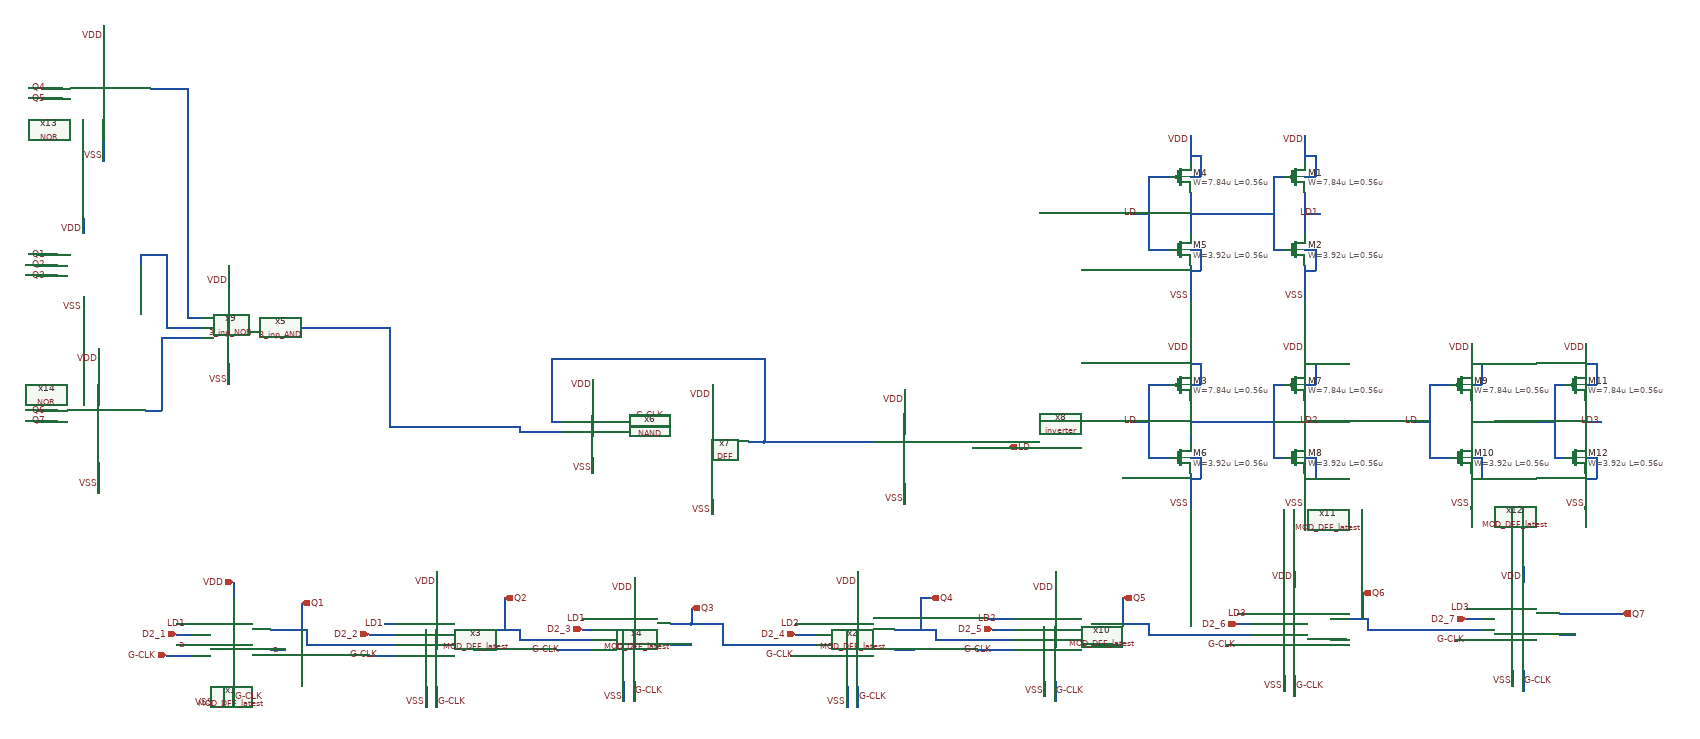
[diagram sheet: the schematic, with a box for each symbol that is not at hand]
v {xschem version=3.1.0 file_version=1.2
}
G {}
K {}
V {}
S {}
E {}
N -1260 -460 -1230 -460 {
lab=a}
N -1440 -490 -1410 -490 {
lab=D2_1}
N -1440 -470 -1410 -470 {
lab=a}
N -1330 -590 -1330 -560 {
lab=VDD}
N -1350 -390 -1350 -360 {
lab=VSS}
N 90 -850 130 -850 {
lab=LD}
N -1440 -510 -1410 -510 {
lab=LD1}
N -1040 -510 -1020 -510 {
lab=LD1}
N -1710 -1220 -1670 -1220 {
lab=Q1}
N -780 -880 -700 -880 {
lab=#net1}
N -310 -1020 -310 -860 {
lab=#net2}
N -720 -1020 -720 -900 {
lab=#net2}
N -720 -900 -700 -900 {
lab=#net2}
N -310 -860 -250 -860 {
lab=#net2}
N -410 -970 -410 -940 {
lab=VDD}
N -640 -980 -640 -950 {
lab=VDD}
N -640 -830 -640 -800 {
lab=VSS}
N -410 -750 -410 -720 {
lab=VSS}
N -940 -610 -940 -560 {
lab=VDD}
N -490 -470 -450 -470 {
lab=#net3}
N -870 -460 -860 -460 {
lab=#net4}
N -660 -500 -640 -500 {
lab=D2_3}
N -1040 -490 -1020 -490 {
lab=D2_2}
N -810 -560 -810 -510 {
lab=Q2}
N -490 -510 -450 -510 {
lab=Q3}
N -1070 -490 -1040 -490 {
lab=D2_2}
N -560 -600 -560 -570 {
lab=VDD}
N -580 -400 -580 -360 {
lab=VSS}
N -1050 -470 -1020 -470 {
lab=Q1}
N -670 -480 -640 -480 {
lab=Q2}
N -520 -910 -490 -910 {
lab=G-CLK}
N -660 -520 -640 -520 {
lab=LD1}
N -810 -510 -810 -500 {
lab=Q2}
N -980 -890 -790 -890 {
lab=#net1}
N -780 -890 -780 -880 {
lab=#net1}
N -790 -890 -780 -890 {
lab=#net1}
N -250 -860 -100 -860 {
lab=#net2}
N 130 -850 160 -850 {
lab=LD}
N -570 -890 -490 -890 {
lab=#net5}
N -960 -390 -960 -350 {
lab=VSS}
N -450 -540 -450 -510 {
lab=Q3}
N -250 -490 -210 -490 {
lab=D2_4}
N -250 -470 -210 -470 {
lab=Q3}
N -130 -610 -130 -560 {
lab=VDD}
N -150 -390 -150 -350 {
lab=VSS}
N -1620 -1290 -1620 -1260 {
lab=VDD}
N -1620 -1140 -1620 -1120 {
lab=VSS}
N -1710 -1200 -1670 -1200 {
lab=Q2}
N -1500 -1220 -1460 -1220 {
lab=#net6}
N -1460 -1220 -1460 -1080 {
lab=#net6}
N -1460 -1080 -1390 -1080 {
lab=#net6}
N -1500 -920 -1470 -920 {
lab=#net7}
N -1470 -1060 -1470 -920 {
lab=#net7}
N -1470 -1060 -1390 -1060 {
lab=#net7}
N -1030 -1060 -1030 -890 {
lab=#net1}
N -1030 -890 -980 -890 {
lab=#net1}
N 120 -520 170 -520 {
lab=LD2}
N 130 -500 170 -500 {
lab=D2_5}
N -10 -560 -10 -500 {
lab=Q4}
N -10 -560 10 -560 {
lab=Q4}
N 130 -480 170 -480 {
lab=Q4}
N 320 -510 360 -510 {
lab=Q5}
N 320 -470 360 -470 {
lab=#net8}
N 250 -610 250 -570 {
lab=VDD}
N 230 -400 230 -370 {
lab=VSS}
N -1510 -1220 -1510 -1200 {
lab=#net6}
N -1510 -1220 -1500 -1220 {
lab=#net6}
N -1710 -1180 -1670 -1180 {
lab=Q3}
N -340 -860 -310 -860 {
lab=#net2}
N -720 -1020 -310 -1020 {
lab=#net2}
N -40 -960 -40 -920 {
lab=VDD}
N -40 -780 -40 -740 {
lab=VSS}
N -1330 -390 -1330 -350 {
lab=G-CLK}
N -1460 -450 -1410 -450 {
lab=G-CLK}
N -940 -390 -940 -350 {
lab=G-CLK}
N -1260 -500 -1190 -500 {
lab=Q1}
N -1200 -550 -1200 -500 {
lab=Q1}
N -870 -500 -780 -500 {
lab=Q2}
N -250 -510 -210 -510 {
lab=LD2}
N -560 -400 -560 -360 {
lab=G-CLK}
N -60 -460 -20 -460 {
lab=#net9}
N -450 -510 -390 -510 {
lab=Q3}
N -130 -390 -130 -350 {
lab=G-CLK}
N -60 -500 20 -500 {
lab=Q4}
N 250 -400 250 -360 {
lab=G-CLK}
N -1270 -1080 -1030 -1080 {
lab=#net1}
N -1030 -1080 -1030 -1060 {
lab=#net1}
N 780 -480 810 -480 {
lab=#net10}
N 600 -510 630 -510 {
lab=D2_6}
N 600 -490 630 -490 {
lab=Q5}
N 710 -610 710 -580 {
lab=VDD}
N 690 -410 690 -380 {
lab=VSS}
N 600 -530 630 -530 {
lab=LD3}
N 710 -410 710 -370 {
lab=G-CLK}
N 780 -520 850 -520 {
lab=Q6}
N 840 -570 840 -520 {
lab=Q6}
N 360 -510 420 -510 {
lab=Q5}
N 380 -560 380 -510 {
lab=Q5}
N 1220 -490 1250 -490 {
lab=#net11}
N 1040 -520 1070 -520 {
lab=D2_7}
N 1040 -500 1070 -500 {
lab=Q6}
N 1150 -620 1150 -590 {
lab=VDD}
N 1130 -420 1130 -390 {
lab=VSS}
N 1040 -540 1070 -540 {
lab=LD3}
N 1150 -420 1150 -380 {
lab=G-CLK}
N 1020 -480 1070 -480 {
lab=#net12}
N 1220 -530 1290 -530 {
lab=Q7}
N 1290 -530 1340 -530 {
lab=Q7}
N -1280 -1070 -1270 -1070 {
lab=#net1}
N -1270 -1080 -1270 -1070 {
lab=#net1}
N -1420 -1100 -1390 -1100 {
lab=#net13}
N -1420 -1540 -1420 -1100 {
lab=#net13}
N -1490 -1540 -1420 -1540 {
lab=#net13}
N -1340 -1200 -1340 -1150 {
lab=VDD}
N -1340 -1010 -1340 -970 {
lab=VSS}
N -1590 -1040 -1590 -1000 {
lab=VDD}
N -1590 -820 -1590 -760 {
lab=VSS}
N -1580 -1660 -1580 -1620 {
lab=VDD}
N -1700 -1540 -1660 -1540 {
lab=Q4}
N -1700 -1520 -1660 -1520 {
lab=Q5}
N -1580 -1440 -1580 -1400 {
lab=VSS}
N -1710 -920 -1670 -920 {
lab=Q6}
N -1710 -900 -1670 -900 {
lab=Q7}
N 430 -1370 430 -1230 {
lab=LD}
N 430 -1230 470 -1230 {
lab=LD}
N 430 -1370 470 -1370 {
lab=LD}
N 510 -1340 510 -1260 {
lab=#net14}
N 510 -1200 510 -1170 {
lab=VSS}
N 510 -1430 510 -1400 {
lab=VDD}
N 510 -1300 540 -1300 {
lab=#net14}
N 400 -1300 430 -1300 {
lab=LD}
N 510 -1370 530 -1370 {
lab=VDD}
N 530 -1410 530 -1370 {
lab=VDD}
N 510 -1410 530 -1410 {
lab=VDD}
N 510 -1230 530 -1230 {
lab=VSS}
N 530 -1230 530 -1190 {
lab=VSS}
N 510 -1190 530 -1190 {
lab=VSS}
N 510 -1450 510 -1430 {
lab=VDD}
N 510 -1170 510 -1130 {
lab=VSS}
N 730 -1340 730 -1260 {
lab=LD1}
N 730 -1200 730 -1170 {
lab=VSS}
N 730 -1430 730 -1400 {
lab=VDD}
N 730 -1300 760 -1300 {
lab=LD1}
N 730 -1370 750 -1370 {
lab=VDD}
N 750 -1410 750 -1370 {
lab=VDD}
N 730 -1410 750 -1410 {
lab=VDD}
N 730 -1230 750 -1230 {
lab=VSS}
N 750 -1230 750 -1190 {
lab=VSS}
N 730 -1190 750 -1190 {
lab=VSS}
N 730 -1450 730 -1430 {
lab=VDD}
N 730 -1170 730 -1130 {
lab=VSS}
N 670 -1370 690 -1370 {
lab=#net14}
N 670 -1370 670 -1230 {
lab=#net14}
N 670 -1230 690 -1230 {
lab=#net14}
N 540 -1300 670 -1300 {
lab=#net14}
N 430 -970 430 -830 {
lab=LD}
N 430 -830 470 -830 {
lab=LD}
N 430 -970 470 -970 {
lab=LD}
N 510 -940 510 -860 {
lab=#net15}
N 510 -800 510 -770 {
lab=VSS}
N 510 -1030 510 -1000 {
lab=VDD}
N 510 -900 540 -900 {
lab=#net15}
N 400 -900 430 -900 {
lab=LD}
N 510 -970 530 -970 {
lab=VDD}
N 530 -1010 530 -970 {
lab=VDD}
N 510 -1010 530 -1010 {
lab=VDD}
N 510 -830 530 -830 {
lab=VSS}
N 530 -830 530 -790 {
lab=VSS}
N 510 -790 530 -790 {
lab=VSS}
N 510 -1050 510 -1030 {
lab=VDD}
N 510 -770 510 -730 {
lab=VSS}
N 730 -940 730 -860 {
lab=LD2}
N 730 -800 730 -770 {
lab=VSS}
N 730 -1030 730 -1000 {
lab=VDD}
N 730 -900 760 -900 {
lab=LD2}
N 730 -970 750 -970 {
lab=VDD}
N 750 -1010 750 -970 {
lab=VDD}
N 730 -1010 750 -1010 {
lab=VDD}
N 730 -830 750 -830 {
lab=VSS}
N 750 -830 750 -790 {
lab=VSS}
N 730 -790 750 -790 {
lab=VSS}
N 730 -1050 730 -1030 {
lab=VDD}
N 730 -770 730 -730 {
lab=VSS}
N 670 -970 690 -970 {
lab=#net15}
N 670 -970 670 -830 {
lab=#net15}
N 670 -830 690 -830 {
lab=#net15}
N 540 -900 670 -900 {
lab=#net15}
N 970 -970 970 -830 {
lab=LD}
N 970 -830 1010 -830 {
lab=LD}
N 970 -970 1010 -970 {
lab=LD}
N 1050 -940 1050 -860 {
lab=#net16}
N 1050 -800 1050 -770 {
lab=VSS}
N 1050 -1030 1050 -1000 {
lab=VDD}
N 1050 -900 1080 -900 {
lab=#net16}
N 940 -900 970 -900 {
lab=LD}
N 1050 -970 1070 -970 {
lab=VDD}
N 1070 -1010 1070 -970 {
lab=VDD}
N 1050 -1010 1070 -1010 {
lab=VDD}
N 1050 -830 1070 -830 {
lab=VSS}
N 1070 -830 1070 -790 {
lab=VSS}
N 1050 -790 1070 -790 {
lab=VSS}
N 1050 -1050 1050 -1030 {
lab=VDD}
N 1050 -770 1050 -730 {
lab=VSS}
N 1270 -940 1270 -860 {
lab=LD3}
N 1270 -800 1270 -770 {
lab=VSS}
N 1270 -1030 1270 -1000 {
lab=VDD}
N 1270 -900 1300 -900 {
lab=LD3}
N 1270 -970 1290 -970 {
lab=VDD}
N 1290 -1010 1290 -970 {
lab=VDD}
N 1270 -1010 1290 -1010 {
lab=VDD}
N 1270 -830 1290 -830 {
lab=VSS}
N 1290 -830 1290 -790 {
lab=VSS}
N 1270 -790 1290 -790 {
lab=VSS}
N 1270 -1050 1270 -1030 {
lab=VDD}
N 1270 -770 1270 -730 {
lab=VSS}
N 1210 -970 1230 -970 {
lab=#net16}
N 1210 -970 1210 -830 {
lab=#net16}
N 1210 -830 1230 -830 {
lab=#net16}
N 1080 -900 1210 -900 {
lab=#net16}
N -1070 -450 -1020 -450 {
lab=G-CLK}
N -780 -480 -670 -480 {
lab=Q2}
N -780 -500 -780 -480 {
lab=Q2}
N -1190 -500 -1190 -470 {
lab=Q1}
N -1190 -470 -1050 -470 {
lab=Q1}
N -390 -470 -250 -470 {
lab=Q3}
N -390 -510 -390 -470 {
lab=Q3}
N 430 -490 600 -490 {
lab=Q5}
N 430 -510 430 -490 {
lab=Q5}
N 420 -510 430 -510 {
lab=Q5}
N 850 -500 1040 -500 {
lab=Q6}
N 850 -520 850 -500 {
lab=Q6}
N 580 -470 630 -470 {
lab=#net17}
N -710 -460 -640 -460 {
lab=G-CLK}
N -260 -450 -210 -450 {
lab=G-CLK}
N 20 -480 130 -480 {
lab=Q4}
N 20 -500 20 -480 {
lab=Q4}
N 100 -460 170 -460 {
lab=#net18}
C {devices/iopin.sym} -1330 -590 3 0 {name=p4 lab=VDD}
C {devices/iopin.sym} -1350 -360 1 0 {name=p5 lab=VSS}
C {devices/lab_wire.sym} -640 -970 0 0 {name=p8 sig_type=std_logic lab=VDD}
C {devices/lab_wire.sym} -410 -950 0 0 {name=p9 sig_type=std_logic lab=VDD}
C {devices/lab_wire.sym} -940 -590 0 0 {name=p11 sig_type=std_logic lab=VDD}
C {devices/lab_wire.sym} -640 -810 0 0 {name=p12 sig_type=std_logic lab=VSS}
C {devices/lab_wire.sym} -410 -730 0 0 {name=p13 sig_type=std_logic lab=VSS}
C {devices/lab_wire.sym} -960 -360 0 0 {name=p15 sig_type=std_logic lab=VSS}
C {devices/opin.sym} -450 -540 3 0 {name=p16 lab=Q3}
C {devices/opin.sym} -1200 -550 3 0 {name=p17 lab=Q1}
C {devices/ipin.sym} -1440 -490 0 0 {name=p18 lab=D2_1}
C {devices/ipin.sym} -1070 -490 0 0 {name=p19 lab=D2_2}
C {devices/lab_wire.sym} -560 -580 0 0 {name=p22 sig_type=std_logic lab=VDD}
C {devices/lab_wire.sym} -580 -370 0 0 {name=p23 sig_type=std_logic lab=VSS}
C {devices/ipin.sym} -660 -500 0 0 {name=p24 lab=D2_3}
C {devices/lab_wire.sym} -1240 -460 0 0 {name=p32 sig_type=std_logic lab=a}
C {devices/ipin.sym} -1460 -450 0 0 {name=p37 lab=G-CLK}
C {devices/lab_wire.sym} -500 -910 0 0 {name=p38 sig_type=std_logic lab=G-CLK}
C {devices/opin.sym} -810 -560 3 0 {name=p39 lab=Q2}
C {devices/opin.sym} 160 -850 0 0 {name=p41 lab=LD}
C {NAND.sym} -550 -880 0 0 {name=x6}
C {devices/ipin.sym} -250 -490 0 0 {name=p21 lab=D2_4}
C {devices/lab_wire.sym} -130 -590 0 0 {name=p25 sig_type=std_logic lab=VDD}
C {devices/lab_wire.sym} -150 -360 0 0 {name=p26 sig_type=std_logic lab=VSS}
C {devices/opin.sym} 10 -560 0 0 {name=p43 lab=Q4}
C {devices/lab_wire.sym} -1620 -1120 0 0 {name=p44 sig_type=std_logic lab=VSS}
C {devices/lab_wire.sym} -1620 -1270 0 0 {name=p45 sig_type=std_logic lab=VDD}
C {devices/ipin.sym} 130 -500 0 0 {name=p51 lab=D2_5}
C {devices/opin.sym} 380 -560 3 0 {name=p52 lab=Q5}
C {devices/lab_wire.sym} 250 -580 0 0 {name=p56 sig_type=std_logic lab=VDD}
C {devices/lab_wire.sym} 230 -380 0 0 {name=p57 sig_type=std_logic lab=VSS}
C {3_inp_NOR.sym} -1300 -1100 0 0 {name=x9}
C {DFF.sym} -340 -890 0 0 {name=x7}
C {devices/lab_wire.sym} -40 -940 0 0 {name=p59 sig_type=std_logic lab=VDD}
C {devices/lab_wire.sym} -40 -750 0 0 {name=p60 sig_type=std_logic lab=VSS}
C {inverter.sym} 50 -840 0 0 {name=x8}
C {MOD_DFF_latest.sym} -1260 -470 0 0 {name=x1}
C {devices/lab_wire.sym} -1420 -470 0 0 {name=p10 sig_type=std_logic lab=a}
C {devices/lab_wire.sym} -1330 -370 2 0 {name=p14 sig_type=std_logic lab=G-CLK}
C {MOD_DFF_latest.sym} -870 -470 0 0 {name=x3}
C {devices/lab_wire.sym} -940 -360 2 0 {name=p31 sig_type=std_logic lab=G-CLK}
C {MOD_DFF_latest.sym} -490 -480 0 0 {name=x4}
C {MOD_DFF_latest.sym} -60 -470 0 0 {name=x2}
C {devices/lab_wire.sym} -560 -380 2 0 {name=p62 sig_type=std_logic lab=G-CLK}
C {MOD_DFF_latest.sym} 320 -480 0 0 {name=x10}
C {devices/lab_wire.sym} -130 -370 2 0 {name=p42 sig_type=std_logic lab=G-CLK}
C {devices/lab_wire.sym} 250 -380 2 0 {name=p63 sig_type=std_logic lab=G-CLK}
C {devices/lab_wire.sym} -1690 -1220 0 0 {name=p27 sig_type=std_logic lab=Q1}
C {devices/lab_wire.sym} -1690 -1200 0 0 {name=p28 sig_type=std_logic lab=Q2}
C {devices/lab_wire.sym} -1690 -1180 0 0 {name=p29 sig_type=std_logic lab=Q3}
C {devices/opin.sym} 840 -570 3 0 {name=p49 lab=Q6}
C {devices/ipin.sym} 600 -510 0 0 {name=p50 lab=D2_6}
C {MOD_DFF_latest.sym} 780 -490 0 0 {name=x11}
C {devices/lab_wire.sym} 710 -390 2 0 {name=p66 sig_type=std_logic lab=G-CLK}
C {devices/opin.sym} 1340 -530 0 0 {name=p69 lab=Q7}
C {devices/ipin.sym} 1040 -520 0 0 {name=p70 lab=D2_7}
C {MOD_DFF_latest.sym} 1220 -500 0 0 {name=x12}
C {devices/lab_wire.sym} 1150 -400 2 0 {name=p73 sig_type=std_logic lab=G-CLK}
C {devices/lab_wire.sym} 710 -600 0 0 {name=p30 sig_type=std_logic lab=VDD}
C {devices/lab_wire.sym} 690 -390 0 0 {name=p46 sig_type=std_logic lab=VSS}
C {devices/lab_wire.sym} 1150 -600 0 0 {name=p67 sig_type=std_logic lab=VDD}
C {devices/lab_wire.sym} 1130 -400 0 0 {name=p68 sig_type=std_logic lab=VSS}
C {3_inp_AND.sym} -1240 -1080 0 0 {name=x5}
C {devices/lab_wire.sym} -1340 -1170 0 0 {name=p47 sig_type=std_logic lab=VDD}
C {devices/lab_wire.sym} -1340 -980 0 0 {name=p48 sig_type=std_logic lab=VSS}
C {NOR.sym} -1510 -1520 0 0 {name=x13}
C {NOR.sym} -1520 -900 0 0 {name=x14}
C {devices/lab_wire.sym} -1580 -1640 0 0 {name=p6 sig_type=std_logic lab=VDD}
C {devices/lab_wire.sym} -1580 -1410 0 0 {name=p74 sig_type=std_logic lab=VSS}
C {devices/lab_wire.sym} -1590 -1020 0 0 {name=p75 sig_type=std_logic lab=VDD}
C {devices/lab_wire.sym} -1590 -780 0 0 {name=p76 sig_type=std_logic lab=VSS}
C {devices/lab_wire.sym} -1690 -1540 0 0 {name=p77 sig_type=std_logic lab=Q4}
C {devices/lab_wire.sym} -1690 -1520 0 0 {name=p78 sig_type=std_logic lab=Q5}
C {devices/lab_wire.sym} -1690 -920 0 0 {name=p79 sig_type=std_logic lab=Q6}
C {devices/lab_wire.sym} -1690 -900 0 0 {name=p80 sig_type=std_logic lab=Q7}
C {symbols/pfet_03v3.sym} 490 -1370 0 0 {name=M4
L=0.56u
W=7.84u
nf=1
m=1
ad="'int((nf+1)/2) * W/nf * 0.18u'"
pd="'2*int((nf+1)/2) * (W/nf + 0.18u)'"
as="'int((nf+2)/2) * W/nf * 0.18u'"
ps="'2*int((nf+2)/2) * (W/nf + 0.18u)'"
nrd="'0.18u / W'" nrs="'0.18u / W'"
sa=0 sb=0 sd=0
model=pfet_03v3
spiceprefix=X
}
C {symbols/nfet_03v3.sym} 490 -1230 0 0 {name=M5
L=0.56u
W=3.92u
nf=1
m=1
ad="'int((nf+1)/2) * W/nf * 0.18u'"
pd="'2*int((nf+1)/2) * (W/nf + 0.18u)'"
as="'int((nf+2)/2) * W/nf * 0.18u'"
ps="'2*int((nf+2)/2) * (W/nf + 0.18u)'"
nrd="'0.18u / W'" nrs="'0.18u / W'"
sa=0 sb=0 sd=0
model=nfet_03v3
spiceprefix=X
}
C {devices/lab_wire.sym} 510 -1440 0 0 {name=p82 sig_type=std_logic lab=VDD}
C {devices/lab_wire.sym} 510 -1140 0 0 {name=p83 sig_type=std_logic lab=VSS}
C {devices/lab_wire.sym} 410 -1300 0 0 {name=p84 sig_type=std_logic lab=LD}
C {symbols/pfet_03v3.sym} 710 -1370 0 0 {name=M1
L=0.56u
W=7.84u
nf=1
m=1
ad="'int((nf+1)/2) * W/nf * 0.18u'"
pd="'2*int((nf+1)/2) * (W/nf + 0.18u)'"
as="'int((nf+2)/2) * W/nf * 0.18u'"
ps="'2*int((nf+2)/2) * (W/nf + 0.18u)'"
nrd="'0.18u / W'" nrs="'0.18u / W'"
sa=0 sb=0 sd=0
model=pfet_03v3
spiceprefix=X
}
C {symbols/nfet_03v3.sym} 710 -1230 0 0 {name=M2
L=0.56u
W=3.92u
nf=1
m=1
ad="'int((nf+1)/2) * W/nf * 0.18u'"
pd="'2*int((nf+1)/2) * (W/nf + 0.18u)'"
as="'int((nf+2)/2) * W/nf * 0.18u'"
ps="'2*int((nf+2)/2) * (W/nf + 0.18u)'"
nrd="'0.18u / W'" nrs="'0.18u / W'"
sa=0 sb=0 sd=0
model=nfet_03v3
spiceprefix=X
}
C {devices/lab_wire.sym} 730 -1440 0 0 {name=p81 sig_type=std_logic lab=VDD}
C {devices/lab_wire.sym} 730 -1140 0 0 {name=p85 sig_type=std_logic lab=VSS}
C {devices/lab_wire.sym} 760 -1300 0 0 {name=p86 sig_type=std_logic lab=LD1}
C {symbols/pfet_03v3.sym} 490 -970 0 0 {name=M3
L=0.56u
W=7.84u
nf=1
m=1
ad="'int((nf+1)/2) * W/nf * 0.18u'"
pd="'2*int((nf+1)/2) * (W/nf + 0.18u)'"
as="'int((nf+2)/2) * W/nf * 0.18u'"
ps="'2*int((nf+2)/2) * (W/nf + 0.18u)'"
nrd="'0.18u / W'" nrs="'0.18u / W'"
sa=0 sb=0 sd=0
model=pfet_03v3
spiceprefix=X
}
C {symbols/nfet_03v3.sym} 490 -830 0 0 {name=M6
L=0.56u
W=3.92u
nf=1
m=1
ad="'int((nf+1)/2) * W/nf * 0.18u'"
pd="'2*int((nf+1)/2) * (W/nf + 0.18u)'"
as="'int((nf+2)/2) * W/nf * 0.18u'"
ps="'2*int((nf+2)/2) * (W/nf + 0.18u)'"
nrd="'0.18u / W'" nrs="'0.18u / W'"
sa=0 sb=0 sd=0
model=nfet_03v3
spiceprefix=X
}
C {devices/lab_wire.sym} 510 -1040 0 0 {name=p87 sig_type=std_logic lab=VDD}
C {devices/lab_wire.sym} 510 -740 0 0 {name=p88 sig_type=std_logic lab=VSS}
C {devices/lab_wire.sym} 410 -900 0 0 {name=p89 sig_type=std_logic lab=LD}
C {symbols/pfet_03v3.sym} 710 -970 0 0 {name=M7
L=0.56u
W=7.84u
nf=1
m=1
ad="'int((nf+1)/2) * W/nf * 0.18u'"
pd="'2*int((nf+1)/2) * (W/nf + 0.18u)'"
as="'int((nf+2)/2) * W/nf * 0.18u'"
ps="'2*int((nf+2)/2) * (W/nf + 0.18u)'"
nrd="'0.18u / W'" nrs="'0.18u / W'"
sa=0 sb=0 sd=0
model=pfet_03v3
spiceprefix=X
}
C {symbols/nfet_03v3.sym} 710 -830 0 0 {name=M8
L=0.56u
W=3.92u
nf=1
m=1
ad="'int((nf+1)/2) * W/nf * 0.18u'"
pd="'2*int((nf+1)/2) * (W/nf + 0.18u)'"
as="'int((nf+2)/2) * W/nf * 0.18u'"
ps="'2*int((nf+2)/2) * (W/nf + 0.18u)'"
nrd="'0.18u / W'" nrs="'0.18u / W'"
sa=0 sb=0 sd=0
model=nfet_03v3
spiceprefix=X
}
C {devices/lab_wire.sym} 730 -1040 0 0 {name=p90 sig_type=std_logic lab=VDD}
C {devices/lab_wire.sym} 730 -740 0 0 {name=p91 sig_type=std_logic lab=VSS}
C {devices/lab_wire.sym} 760 -900 0 0 {name=p92 sig_type=std_logic lab=LD2}
C {symbols/pfet_03v3.sym} 1030 -970 0 0 {name=M9
L=0.56u
W=7.84u
nf=1
m=1
ad="'int((nf+1)/2) * W/nf * 0.18u'"
pd="'2*int((nf+1)/2) * (W/nf + 0.18u)'"
as="'int((nf+2)/2) * W/nf * 0.18u'"
ps="'2*int((nf+2)/2) * (W/nf + 0.18u)'"
nrd="'0.18u / W'" nrs="'0.18u / W'"
sa=0 sb=0 sd=0
model=pfet_03v3
spiceprefix=X
}
C {symbols/nfet_03v3.sym} 1030 -830 0 0 {name=M10
L=0.56u
W=3.92u
nf=1
m=1
ad="'int((nf+1)/2) * W/nf * 0.18u'"
pd="'2*int((nf+1)/2) * (W/nf + 0.18u)'"
as="'int((nf+2)/2) * W/nf * 0.18u'"
ps="'2*int((nf+2)/2) * (W/nf + 0.18u)'"
nrd="'0.18u / W'" nrs="'0.18u / W'"
sa=0 sb=0 sd=0
model=nfet_03v3
spiceprefix=X
}
C {devices/lab_wire.sym} 1050 -1040 0 0 {name=p93 sig_type=std_logic lab=VDD}
C {devices/lab_wire.sym} 1050 -740 0 0 {name=p94 sig_type=std_logic lab=VSS}
C {devices/lab_wire.sym} 950 -900 0 0 {name=p95 sig_type=std_logic lab=LD}
C {symbols/pfet_03v3.sym} 1250 -970 0 0 {name=M11
L=0.56u
W=7.84u
nf=1
m=1
ad="'int((nf+1)/2) * W/nf * 0.18u'"
pd="'2*int((nf+1)/2) * (W/nf + 0.18u)'"
as="'int((nf+2)/2) * W/nf * 0.18u'"
ps="'2*int((nf+2)/2) * (W/nf + 0.18u)'"
nrd="'0.18u / W'" nrs="'0.18u / W'"
sa=0 sb=0 sd=0
model=pfet_03v3
spiceprefix=X
}
C {symbols/nfet_03v3.sym} 1250 -830 0 0 {name=M12
L=0.56u
W=3.92u
nf=1
m=1
ad="'int((nf+1)/2) * W/nf * 0.18u'"
pd="'2*int((nf+1)/2) * (W/nf + 0.18u)'"
as="'int((nf+2)/2) * W/nf * 0.18u'"
ps="'2*int((nf+2)/2) * (W/nf + 0.18u)'"
nrd="'0.18u / W'" nrs="'0.18u / W'"
sa=0 sb=0 sd=0
model=nfet_03v3
spiceprefix=X
}
C {devices/lab_wire.sym} 1270 -1040 0 0 {name=p96 sig_type=std_logic lab=VDD}
C {devices/lab_wire.sym} 1270 -740 0 0 {name=p97 sig_type=std_logic lab=VSS}
C {devices/lab_wire.sym} 1300 -900 0 0 {name=p98 sig_type=std_logic lab=LD3}
C {devices/lab_wire.sym} -1420 -510 0 0 {name=p2 sig_type=std_logic lab=LD1}
C {devices/lab_wire.sym} -1040 -510 0 0 {name=p3 sig_type=std_logic lab=LD1}
C {devices/lab_wire.sym} -650 -520 0 0 {name=p7 sig_type=std_logic lab=LD1}
C {devices/lab_wire.sym} -240 -510 0 0 {name=p40 sig_type=std_logic lab=LD2}
C {devices/lab_wire.sym} 140 -520 0 0 {name=p55 sig_type=std_logic lab=LD2}
C {devices/lab_wire.sym} 620 -530 0 0 {name=p61 sig_type=std_logic lab=LD3}
C {devices/lab_wire.sym} 1050 -540 0 0 {name=p99 sig_type=std_logic lab=LD3}
C {devices/lab_wire.sym} -1050 -450 0 0 {name=p1 sig_type=std_logic lab=G-CLK}
C {devices/lab_wire.sym} -700 -460 0 0 {name=p20 sig_type=std_logic lab=G-CLK}
C {devices/lab_wire.sym} -250 -450 0 0 {name=p33 sig_type=std_logic lab=G-CLK}
C {devices/lab_wire.sym} 130 -460 0 0 {name=p34 sig_type=std_logic lab=G-CLK}
C {devices/lab_wire.sym} 600 -470 0 0 {name=p35 sig_type=std_logic lab=G-CLK}
C {devices/lab_wire.sym} 1040 -480 0 0 {name=p36 sig_type=std_logic lab=G-CLK}
